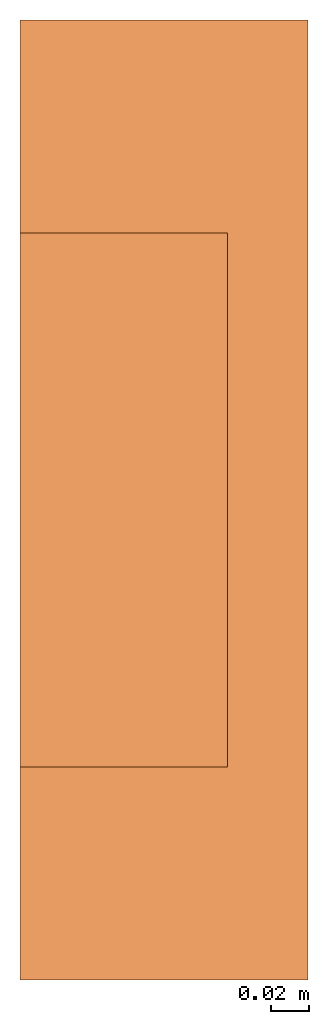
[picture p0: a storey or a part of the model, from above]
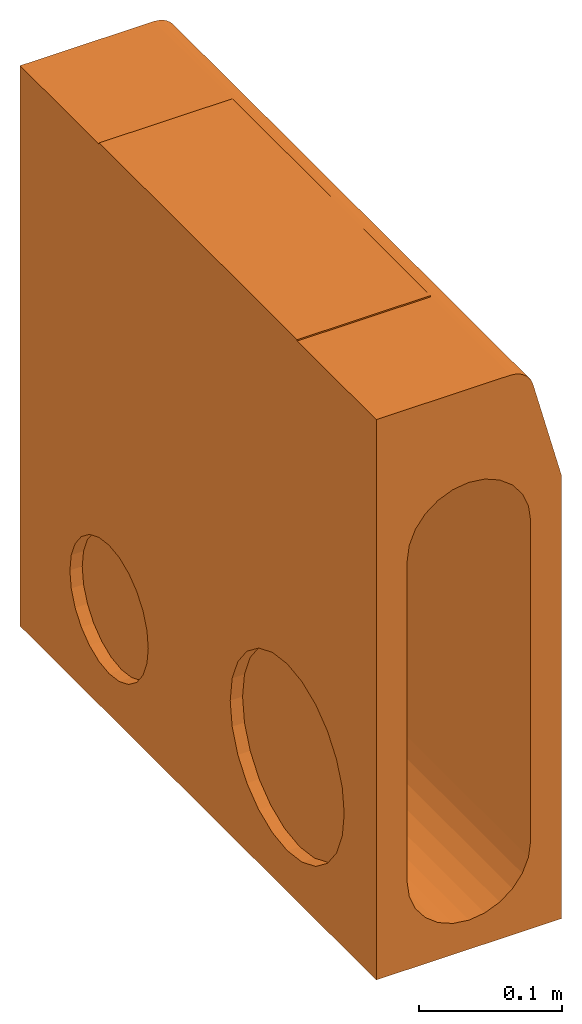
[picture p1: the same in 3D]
Properties of the parts of a building model (IFC2X3)

# File
Description: ViewDefinition [CoordinationView]
File name: 4927 - Access Unit - 500mm LG.ifc
Time: 2013-09-18T16:21:13
Written by: Autodesk Revit 2013
Made in: 20120221_2030(x64)

# IfcProject, Project Number
LongName: Project Name; Phase: Project Status

# IfcSite, Default
RefLatitude: 42, 21, 30, 344238; RefLongitude: -71, -3, -35, -194702; RefElevation: 0 mm

# IfcBuilding
Pset_BuildingCommon - NumberOfStoreys: 2
Other - Project Number: Project Number; Project Name: Project Name; Project Issue Date: Issue Date; Client Name: Owner; Project Address: Enter address here; Project Status: Project Status

# IfcBuildingStorey (2)
Graphics - Symbol: M_Level Head - Circle: M_Level Head - Circle; Color: 0; Line Pattern: Center; Symbol at End 1 Default: no; Symbol at End 2 Default: yes; Line Weight: 1
Constraints - Elevation Base: 0
Identity Data - Building Story: yes; Structural: no
Dimensions - Computation Height: 0 mm
Name | LongName = Name | Elevation (mm) = Constraints, Elevation (mm)
T.O. Fnd. Wall | T.O. Fnd. Wall | -300
Level 1 | Level 1 | 0

# IfcBuildingElementProxy: 4927 - Access Unit - 500mm LG, Civil-Drainage-Channel-ACO-KerbDrain-HB480(amar):4927 - Access Unit - 500mm LG:4927 - Access Unit - 500mm LG:481515
In: T.O. Fnd. Wall
Material: ACO Polymer Concrete., Iron, Cast
Other - Revision: 1; CreatedBy: www.aco.co.uk
Green Building Properties - Channel Recycled Material Content: 20% minimum; Access Cover/Frame Recycled Material Content: Between 40% - 90%; End Cap Recyclable: N/A; Access Cover/Frame Recyclable: Fully recyclable; Channel Recyclable: Fully recyclable; End Cap Recycled Material Content: N/A
Constraints - Level: Level: Level 1; Moves With Nearby Elements: no
Phasing - Phase Created: Phase 1
Dimensions - Volume: 17031969 mm3; Mitre Void End: -2460 mm; Mitre Small End: 487 mm; Straight Void Start: 0 mm; Void Start I/O: 0 mm; Junction Start: 0 mm; I/O endcap void depth: 2000 mm; Mitre Void Start: -2455 mm; Void Depth: -355 mm; Junction End: 150 mm; Void End I/O: 150 mm; junction void depth: 2000 mm; Mitre Long end: 500 mm; Void Length: 500 mm; Void Width: 150 mm
Pset_BuildingElementProxyCommon - Reference: 4927 - Access Unit - 500mm LG
Data - Drainage Slot Width: N/A; Drainage Slot Intake area: N/A; Product Dimensions: 500mm x 150mm x 480mm (LxWxH); Hydraulic Performance: http://www.aco.co.uk/download.php?id=120; Concrete Surround Volume - Load Class A 15 - D 400 - Concrete Pavement: 0.19m³/m; Channel C.S.A: 0.04m²; Concrete Surround Volume - Load Class A 15 - D 400 - Grass or Asphalt Pavement: 0.18m³/m; Product Weight: 36.7 Kg; Installation - Concrete Grade: Refer to brochure; ACO Hydraulic Design Software: http://www.acodesign.co.uk; Product Standard: BS EN 1433:2002, CE marked, Kitemarked; Connection Pipe O.D: N/A; Load Class: A 15 - D 400; Invert Depth: 455mm
Construction - Closing end cap: no; 7-6m external mitre: no; Bus stop kerb: no; Centre Stone: no; LH inlet/outlet end cap: no; 10-8m external mitre: no; HB480-500: no; RH inlet/outlet end cap: no; LH BS transition kerb: no; RH drop kerb: no; Junction access unit: no; Access Unit: yes; Junction channel: no; 25-11m external mitre: no; cable loop: no; perforated centre stone: no; KDHB480 500_blindunit: no; LH drop kerb: no; Junction end cap: no; 25-11m internal mitre: no; RH BS transition kerb: no
Identity Data - Address: ACO Business Park, Hitchin Road, Shefford, Bedfordshire, United Kingdom SG17 5TE; Product brochure: http://www.aco.co.uk/download.php?id=120; Price: POA - contact ACO; Telephone: +44 (0)1462 816666; Product Code: 4927; Model Description: Combined kerb and drainage system; OmniClass Title: Rainwater Removal; Model: ACO KerbDrain HB480; Type Comments: ACO KerbDrain HB480 half battered access unit 500mm long; Installation guidelines: http://www.aco.co.uk/download.php?id=120; Assembly Description: Rain Water Drainage; e-mail Sales: customersupport@aco.co.uk; OmniClass Number: 23.70.50.24; URL: www.aco.co.uk; Maintenance guidelines: http://www.aco.co.uk/download.php?id=120; e-mail Technical: technical@aco.co.uk; Fax: +44 (0)1462 815895; Assembly Code: D2040; Product Page URL: http://www.aco.co.uk/product_detail.php?id=3; Cost: 0; Manufacturer: ACO Technologies plc - ACO Water Management Division
General - TagNumber: 0.000000; SerialNumber: 0.000000
Materials and Finishes - Access Cover/Frame Material: Ductile Iron; Connection Pipe Material Colour: N/A; Access Cover/Frame Finish: Water Based Paint Coating; Connection Pipe Material: N/A; Access Cover/Frame Colour: Black; Channel Colour: Grey; End Cap Material: N/A; Channel Material: Vienite® Synthetic Resin Concrete; End Cap Colour: N/A

# IfcOpeningElement: Opening (3)
In: Level 1
Structural - Structural: no; Enable Analytical Model: no
Constraints - Height Offset From Level: 0 mm; Related to Mass: no; Level: Level: Level 1; Room Bounding: yes
Dimensions - Perimeter: 9790 mm; Thickness: 400 mm; Volume: 2334075000 mm3; Area: 5901750 mm2
Phasing - Phase Created: Phase 1
Analytical Properties - Thermal Resistance (R): 0.477897; Roughness: 1; Heat Transfer Coefficient (U): 2.0925; Absorptance: 0.1; Thermal mass: 543920
Construction - Function: 0; Default Thickness: 400 mm
Materials and Finishes - Structural Material: Earth
Graphics - Coarse Scale Fill Color: 0

# IfcSlab: Floor:Generic Floor - 400mm, Floor:Generic Floor - 400mm:136426
In: Level 1
PredefinedType: FLOOR; Material: Earth 400 mm
Structural - Structural: no; Enable Analytical Model: no
Constraints - Height Offset From Level: 0 mm; Related to Mass: no; Level: Level: Level 1; Room Bounding: yes
Dimensions - Perimeter: 9790 mm; Thickness: 400 mm; Volume: 2334075000 mm3; Area: 5901750 mm2
Phasing - Phase Created: Phase 1
Pset_SlabCommon - Reference: Generic Floor - 400mm; IsExternal: no; LoadBearing: yes
Analytical Properties - Thermal Resistance (R): 0.477897; Roughness: 1; Heat Transfer Coefficient (U): 2.0925; Absorptance: 0.1; Thermal mass: 543920
Construction - Function: 0; Default Thickness: 400 mm
Materials and Finishes - Structural Material: Earth
Graphics - Coarse Scale Fill Color: 0
